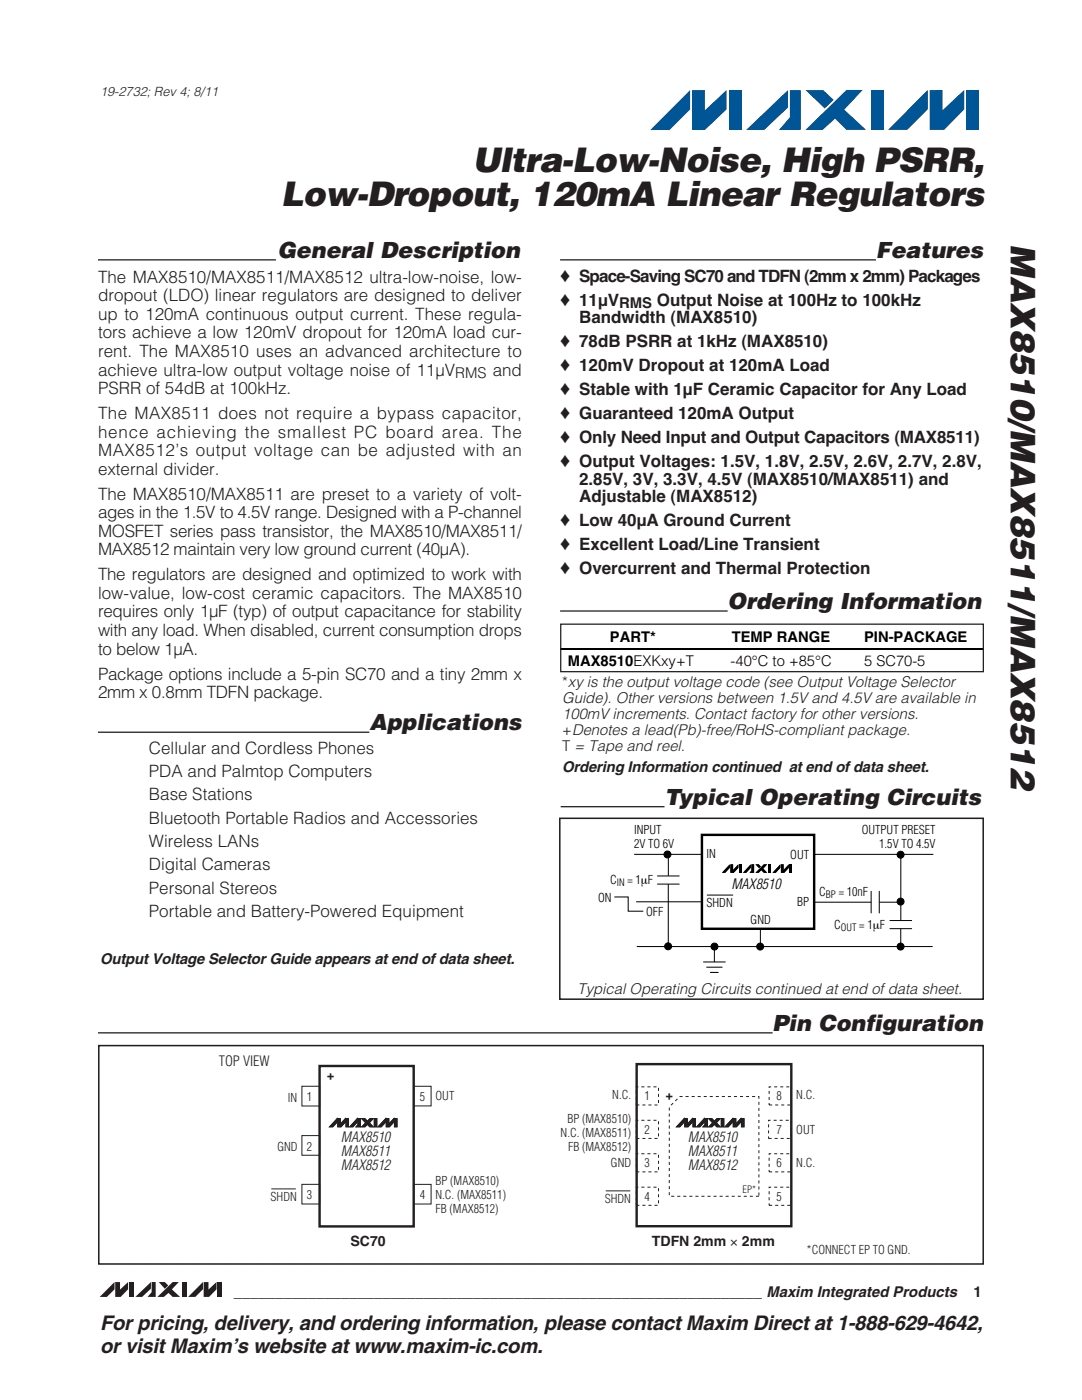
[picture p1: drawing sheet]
<svg xmlns="http://www.w3.org/2000/svg" width="216mm" height="279mm" viewBox="0 0 216 279" stroke-linecap="round" stroke-linejoin="round" font-family="sans-serif">
<defs><g id="words">
<g font-size="6.9" fill="#231f20">
<text x="94.3" y="34.3">Ultra-Low-Noise, High PSRR,</text>
<text x="56.1" y="41">Low-Dropout, 120mA Linear Regulators</text>
<text x="201.7" y="48.7" transform="rotate(90 201.7 48.7)">MAX8510/MAX8511/MAX8512</text>
</g>
<g font-size="4.5" fill="#231f20">
<text x="55.4" y="51.5">General Description</text>
<text x="174.8" y="51.5">Features</text>
<text x="145.2" y="121.5">Ordering Information</text>
<text x="73.7" y="145.7">Applications</text>
<text x="132.6" y="160.6">Typical Operating Circuits</text>
<text x="154.2" y="205.7">Pin Configuration</text>
</g>
<g font-size="4.1" fill="#231f20">
<text x="20" y="265.4">For pricing, delivery, and ordering information, please contact Maxim Direct at 1-888-629-4642,</text>
<text x="20" y="270">or visit Maxim’s website at www.maxim-ic.com.</text>
</g>
<g font-size="3.4" fill="#231f20">
<text x="19.6" y="56.4">The MAX8510/MAX8511/MAX8512 ultra-low-noise, low-</text>
<text x="111.8" y="56.2">♦ Space-Saving SC70 and TDFN (2mm x 2mm) Packages</text>
<text x="19.6" y="60.1">dropout (LDO) linear regulators are designed to deliver</text>
<text x="19.6" y="63.8">up to 120mA continuous output current. These regula-</text>
<text x="111.8" y="61">♦ 11µV</text>
<text x="115.6" y="64.5">Bandwidth (MAX8510)</text>
<text x="131.1" y="61">Output Noise at 100Hz to 100kHz</text>
<text x="19.6" y="67.6">tors achieve a low 120mV dropout for 120mA load cur-</text>
<text x="19.6" y="71.3">rent. The MAX8510 uses an advanced architecture to</text>
<text x="111.8" y="69.3">♦ 78dB PSRR at 1kHz (MAX8510)</text>
<text x="19.6" y="75">achieve ultra-low output voltage noise of 11µV</text>
<text x="98.3" y="75">and</text>
<text x="111.8" y="74.1">♦ 120mV Dropout at 120mA Load</text>
<text x="19.6" y="78.7">PSRR of 54dB at 100kHz.</text>
<text x="19.6" y="83.6">The MAX8511 does not require a bypass capacitor,</text>
<text x="111.8" y="78.9">♦ Stable with 1µF Ceramic Capacitor for Any Load</text>
<text x="111.8" y="83.7">♦ Guaranteed 120mA Output</text>
<text x="19.6" y="87.3">hence achieving the smallest PC board area. The</text>
<text x="111.8" y="88.5">♦ Only Need Input and Output Capacitors (MAX8511)</text>
<text x="19.6" y="91">MAX8512’s output voltage can be adjusted with an</text>
<text x="19.6" y="94.8">external divider.</text>
<text x="111.8" y="93.2">♦ Output Voltages: 1.5V, 1.8V, 2.5V, 2.6V, 2.7V, 2.8V,</text>
<text x="19.6" y="99.7">The MAX8510/MAX8511 are preset to a variety of volt-</text>
<text x="115.6" y="96.8">2.85V, 3V, 3.3V, 4.5V (MAX8510/MAX8511) and</text>
<text x="115.6" y="100.3">Adjustable (MAX8512)</text>
<text x="19.6" y="103.4">ages in the 1.5V to 4.5V range. Designed with a P-channel</text>
<text x="19.6" y="107.1">MOSFET series pass transistor, the MAX8510/MAX8511/</text>
<text x="111.8" y="105">♦ Low 40µA Ground Current</text>
<text x="19.6" y="110.8">MAX8512 maintain very low ground current (40µA).</text>
<text x="111.8" y="109.8">♦ Excellent Load/Line Transient</text>
<text x="19.6" y="115.8">The regulators are designed and optimized to work with</text>
<text x="19.6" y="119.5">low-value, low-cost ceramic capacitors. The MAX8510</text>
<text x="111.8" y="114.6">♦ Overcurrent and Thermal Protection</text>
<text x="19.6" y="123.2">requires only 1µF (typ) of output capacitance for stability</text>
<text x="19.6" y="126.9">with any load. When disabled, current consumption drops</text>
<text x="19.6" y="130.6">to below 1µA.</text>
<text x="19.6" y="135.6">Package options include a 5-pin SC70 and a tiny 2mm x</text>
<text x="19.6" y="139.3">2mm x 0.8mm TDFN package.</text>
<text x="29.7" y="150.4">Cellular and Cordless Phones</text>
<text x="29.7" y="155">PDA and Palmtop Computers</text>
<text x="29.7" y="159.7">Base Stations</text>
<text x="29.7" y="164.4">Bluetooth Portable Radios and Accessories</text>
<text x="29.7" y="169">Wireless LANs</text>
<text x="29.7" y="173.7">Digital Cameras</text>
<text x="29.7" y="178.3">Personal Stereos</text>
<text x="29.7" y="183">Portable and Battery-Powered Equipment</text>
</g>
<g font-size="3" fill="#231f20">
<text x="123.5" y="61.5">RMS</text>
<text x="90.8" y="75.4">RMS</text>
<text x="112.2" y="137.1">*xy is the output voltage code (see Output Voltage Selector</text>
<text x="112.2" y="140.3">Guide). Other versions between 1.5V and 4.5V are available in</text>
<text x="112.2" y="143.4">100mV increments. Contact factory for other versions.</text>
<text x="112.2" y="146.6">+Denotes a lead(Pb)-free/RoHS-compliant package.</text>
<text x="112.2" y="149.8">T = Tape and reel.</text>
<text x="112.2" y="154">Ordering Information continued at end of data sheet.</text>
<text x="20" y="192.3">Output Voltage Selector Guide appears at end of data sheet.</text>
<text x="115.2" y="198.3">Typical Operating Circuits continued at end of data sheet.</text>
<text x="46.7" y="258.8">________________________________________________________________ Maxim Integrated Products</text>
<text x="194.3" y="258.8">1</text>
</g>
<g font-size="2.9">
<text x="121.7" y="128.2">PART*</text>
<text x="146" y="128.2">TEMP RANGE</text>
<text x="172.4" y="128.2">PIN-PACKAGE</text>
<text x="113.3" y="132.9">MAX8510EXKxy+T</text>
<text x="145.8" y="132.9">-40°C to +85°C</text>
<text x="172.4" y="132.9">5 SC70-5</text>
</g>
<text font-size="2.8" x="145.9" y="177.4">MAX8510</text>
<g font-size="2.8" fill="#231f20">
<text x="43.7" y="212.8">TOP VIEW</text>
<text x="68" y="228">MAX8510</text>
<text x="137.3" y="228">MAX8510</text>
<text x="68" y="230.8">MAX8511</text>
<text x="68" y="233.6">MAX8512</text>
<text x="137.3" y="230.8">MAX8511</text>
<text x="137.3" y="233.6">MAX8512</text>
<text x="69.9" y="248.6">SC70</text>
<text x="130.1" y="248.7">TDFN 2mm × 2mm</text>
</g>
<text font-size="2.6" fill="#231f20" x="20" y="19.2">19-2732; Rev 4; 8/11</text>
<g font-size="2.4">
<text x="126.5" y="166.4">INPUT</text>
<text x="172" y="166.5">OUTPUT PRESET</text>
<text x="126.5" y="169.2">2V TO 6V</text>
<text x="141" y="171.3">IN</text>
<text x="157.7" y="171.4">OUT</text>
<text x="175.4" y="169.3">1.5V TO 4.5V</text>
<text x="121.7" y="176.4">C</text>
<text x="125.2" y="176.4">= 1μF</text>
<text x="163.5" y="178.9">C</text>
<text x="167.4" y="178.9">= 10nF</text>
<text x="119.3" y="180">ON</text>
<text x="128.9" y="182.7">OFF</text>
<text x="141" y="181">SHDN</text>
<text x="149.8" y="184.4">GND</text>
<text x="159" y="180.8">BP</text>
<text x="166.5" y="185.5">C</text>
<text x="171.5" y="185.5">= 1μF</text>
</g>
<g font-size="2.4" fill="#231f20">
<text x="65.3" y="214" transform="rotate(90 65.3 214)">+</text>
<text x="57.4" y="220">IN</text>
<text x="61.2" y="219.6">1</text>
<text x="83.8" y="219.6">5</text>
<text x="86.9" y="219.6">OUT</text>
<text x="122.2" y="219.4">N.C.</text>
<text x="128.6" y="219.5">1</text>
<text x="132.9" y="218.1" transform="rotate(90 132.9 218.1)">+</text>
<text x="155" y="219.5">8</text>
<text x="158.9" y="219.4">N.C.</text>
<text x="111.9" y="226.9">N.C. (MAX8511)</text>
<text x="113.2" y="224.1">BP (MAX8510)</text>
<text x="128.6" y="226.2">2</text>
<text x="154.9" y="226.2">7</text>
<text x="158.9" y="226.3">OUT</text>
<text x="55.3" y="229.7">GND</text>
<text x="61.2" y="229.6">2</text>
<text x="113.3" y="229.7">FB (MAX8512)</text>
<text x="121.9" y="232.9">GND</text>
<text x="128.6" y="232.9">3</text>
<text x="155" y="232.9">6</text>
<text x="158.9" y="232.9">N.C.</text>
<text x="54" y="239.6">SHDN</text>
<text x="61.2" y="239.4">3</text>
<text x="83.8" y="239.4">4</text>
<text x="86.9" y="236.4">BP (MAX8510)</text>
<text x="86.9" y="239.3">N.C. (MAX8511)</text>
<text x="128.6" y="239.7">4</text>
<text x="155" y="239.7">5</text>
<text x="86.9" y="242.1">FB (MAX8512)</text>
<text x="120.7" y="240">SHDN</text>
<text x="161" y="250.2">*CONNECT EP TO GND.</text>
</g>
<g font-size="2">
<text x="123.1" y="176.8">IN</text>
<text x="164.8" y="179.3">BP</text>
<text x="167.8" y="185.9">OUT</text>
</g>
<text font-size="2" fill="#231f20" x="148.2" y="238.1">EP*</text>
</g></defs>
<path d="M19.6 51.9h35.5M111.8 51.9h63M19.6 146.1h54.1" fill="none" stroke="#231f20" stroke-width=".26"/>
<path d="M19.9 254h25.9v5.1h-25.9z" fill="#fff"/>
<g fill="#231f20">
<path d="M27 258.8l3.1-2.9v1.3l-1.7 1.6z"/>
<path d="M30.3 255.9h.8v2.9h-1.7l.9-.9z"/>
<path d="M31.7 255.9h1.2l.7 .6-.7 .7z"/>
<path d="M31.4 258.8l3.1-2.9h1.2l-1.4 1.4 1.6 1.5h-1.4l-.9-.8-.9 .8z"/>
<path d="M22.9 255.9v1.4l-1.6 1.5h-1.4z"/>
<path d="M23 255.9h1v1.5l1.6-1.5v1.4l-1.5 1.5h-1.1z"/>
<path d="M25.7 255.9h1v2.9h-1z"/>
<path d="M36.3 255.9h.9v2.9h-.9z"/>
<path d="M40.5 255.9v1.4l-1.5 1.5h-1.5z"/>
<path d="M40.6 255.9h1v1.5l1.6-1.5v1.4l-1.5 1.5h-1.1z"/>
<path d="M43.3 255.9h1v2.9h-1z"/>
</g>
<path d="M60.2 226.6h3.6v4h-3.6z" fill="#fff"/>
<path d="M60.2 226.6h3.6v4h-3.6z" fill="none" stroke="#231f20" stroke-width=".2"/>
<path d="M60.2 236.4h3.6v3.9h-3.6z" fill="#fff"/>
<path d="M60.2 236.4h3.6v3.9h-3.6z" fill="none" stroke="#231f20" stroke-width=".2"/>
<path d="M82.5 236.4h3.5v3.9h-3.5z" fill="#fff"/>
<path d="M82.5 236.4h3.5v3.9h-3.5z" fill="none" stroke="#231f20" stroke-width=".2"/>
<path d="M60.2 216.8h3.6v3.9h-3.6z" fill="#fff"/>
<path d="M60.2 216.8h3.6v3.9h-3.6z" fill="none" stroke="#231f20" stroke-width=".2"/>
<path d="M82.5 216.8h3.5v3.9h-3.5z" fill="#fff"/>
<path d="M82.5 216.8h3.5v3.9h-3.5z" fill="none" stroke="#231f20" stroke-width=".2"/>
<path d="M63.8 212.7h18.7v32.1h-18.7z" fill="none" stroke="#231f20" stroke-width=".48"/>
<path d="M67.3 223.3v.6l-.9 1h-.6z" fill="#231f20"/>
<path d="M67.3 223.3v.6l-.9 1h-.6z" fill="none" stroke="#231f20" stroke-width=".2"/>
<path d="M67.3 223.3v.6l-.9 1h-.6z" fill="#231f20"/>
<path d="M67.3 223.3v.6l-.9 1h-.6z" fill="none" stroke="#231f20" stroke-width=".2"/>
<path d="M67.4 223.3h.5v1l1-1v.6l-.9 1h-.6z" fill="#231f20"/>
<path d="M67.4 223.3h.5v1l1-1v.6l-.9 1h-.6z" fill="none" stroke="#231f20" stroke-width=".2"/>
<path d="M67.4 223.3h.5v1l1-1v.6l-.9 1h-.6z" fill="#231f20"/>
<path d="M67.4 223.3h.5v1l1-1v.6l-.9 1h-.6z" fill="none" stroke="#231f20" stroke-width=".2"/>
<path d="M69 223.3h.5v1.6h-.5z" fill="#231f20"/>
<path d="M69 223.3h.5v1.6h-.5z" fill="none" stroke="#231f20" stroke-width=".2"/>
<path d="M69 223.3h.5v1.6h-.5z" fill="#231f20"/>
<path d="M69 223.3h.5v1.6h-.5z" fill="none" stroke="#231f20" stroke-width=".2"/>
<path d="M71.3 223.3v.6l-.9 1h-.6z" fill="#231f20"/>
<path d="M71.3 223.3v.6l-.9 1h-.6z" fill="none" stroke="#231f20" stroke-width=".2"/>
<path d="M71.3 223.3v.6l-.9 1h-.6z" fill="#231f20"/>
<path d="M71.3 223.3v.6l-.9 1h-.6z" fill="none" stroke="#231f20" stroke-width=".2"/>
<path d="M71.4 223.3h.5v1.6h-.8l.3-.4z" fill="#231f20"/>
<path d="M71.4 223.3h.5v1.6h-.8l.3-.4z" fill="none" stroke="#231f20" stroke-width=".2"/>
<path d="M71.4 223.3h.5v1.6h-.8l.3-.4z" fill="#231f20"/>
<path d="M71.4 223.3h.5v1.6h-.8l.3-.4z" fill="none" stroke="#231f20" stroke-width=".2"/>
<path d="M73.8 223.3h.6l-.7 .8 .7 .8h-.6l-.5-.5-.5 .5h-.6z" fill="#231f20"/>
<path d="M73.8 223.3h.6l-.7 .8 .7 .8h-.6l-.5-.5-.5 .5h-.6z" fill="none" stroke="#231f20" stroke-width=".2"/>
<path d="M73.8 223.3h.6l-.7 .8 .7 .8h-.6l-.5-.5-.5 .5h-.6z" fill="#231f20"/>
<path d="M73.8 223.3h.6l-.7 .8 .7 .8h-.6l-.5-.5-.5 .5h-.6z" fill="none" stroke="#231f20" stroke-width=".2"/>
<path d="M72.2 223.3h.6l.4 .4-.3 .3z" fill="#231f20"/>
<path d="M72.2 223.3h.6l.4 .4-.3 .3z" fill="none" stroke="#231f20" stroke-width=".2"/>
<path d="M72.2 223.3h.6l.4 .4-.3 .3z" fill="#231f20"/>
<path d="M72.2 223.3h.6l.4 .4-.3 .3z" fill="none" stroke="#231f20" stroke-width=".2"/>
<path d="M74.7 223.3h.5v1.6h-.5z" fill="#231f20"/>
<path d="M74.7 223.3h.5v1.6h-.5z" fill="none" stroke="#231f20" stroke-width=".2"/>
<path d="M74.7 223.3h.5v1.6h-.5z" fill="#231f20"/>
<path d="M74.7 223.3h.5v1.6h-.5z" fill="none" stroke="#231f20" stroke-width=".2"/>
<path d="M77 223.3v.6l-.9 1h-.7z" fill="#231f20"/>
<path d="M77 223.3v.6l-.9 1h-.7z" fill="none" stroke="#231f20" stroke-width=".2"/>
<path d="M77 223.3v.6l-.9 1h-.7z" fill="#231f20"/>
<path d="M77 223.3v.6l-.9 1h-.7z" fill="none" stroke="#231f20" stroke-width=".2"/>
<path d="M77.1 223.3h.5v1l1-1v.6l-.9 1h-.6z" fill="#231f20"/>
<path d="M77.1 223.3h.5v1l1-1v.6l-.9 1h-.6z" fill="none" stroke="#231f20" stroke-width=".2"/>
<path d="M77.1 223.3h.5v1l1-1v.6l-.9 1h-.6z" fill="#231f20"/>
<path d="M77.1 223.3h.5v1l1-1v.6l-.9 1h-.6z" fill="none" stroke="#231f20" stroke-width=".2"/>
<path d="M78.7 223.3h.5v1.6h-.5z" fill="#231f20"/>
<path d="M78.7 223.3h.5v1.6h-.5z" fill="none" stroke="#231f20" stroke-width=".2"/>
<path d="M78.7 223.3h.5v1.6h-.5z" fill="#231f20"/>
<path d="M78.7 223.3h.5v1.6h-.5z" fill="none" stroke="#231f20" stroke-width=".2"/>
<path d="M136.5 223.3v.6l-.9 1h-.6z" fill="#231f20"/>
<path d="M136.5 223.3v.6l-.9 1h-.6z" fill="none" stroke="#231f20" stroke-width=".2"/>
<path d="M136.5 223.3v.6l-.9 1h-.6z" fill="#231f20"/>
<path d="M136.5 223.3v.6l-.9 1h-.6z" fill="none" stroke="#231f20" stroke-width=".2"/>
<path d="M136.6 223.3h.6v1l1-1v.6l-.9 1h-.7z" fill="#231f20"/>
<path d="M136.6 223.3h.6v1l1-1v.6l-.9 1h-.7z" fill="none" stroke="#231f20" stroke-width=".2"/>
<path d="M136.6 223.3h.6v1l1-1v.6l-.9 1h-.7z" fill="#231f20"/>
<path d="M136.6 223.3h.6v1l1-1v.6l-.9 1h-.7z" fill="none" stroke="#231f20" stroke-width=".2"/>
<path d="M138.3 223.3h.5v1.6h-.5z" fill="#231f20"/>
<path d="M138.3 223.3h.5v1.6h-.5z" fill="none" stroke="#231f20" stroke-width=".2"/>
<path d="M138.3 223.3h.5v1.6h-.5z" fill="#231f20"/>
<path d="M138.3 223.3h.5v1.6h-.5z" fill="none" stroke="#231f20" stroke-width=".2"/>
<path d="M140.5 223.3v.6l-.8 1h-.7z" fill="#231f20"/>
<path d="M140.5 223.3v.6l-.8 1h-.7z" fill="none" stroke="#231f20" stroke-width=".2"/>
<path d="M140.5 223.3v.6l-.8 1h-.7z" fill="#231f20"/>
<path d="M140.5 223.3v.6l-.8 1h-.7z" fill="none" stroke="#231f20" stroke-width=".2"/>
<path d="M140.7 223.3h.5v1.6h-.9l.4-.4z" fill="#231f20"/>
<path d="M140.7 223.3h.5v1.6h-.9l.4-.4z" fill="none" stroke="#231f20" stroke-width=".2"/>
<path d="M140.7 223.3h.5v1.6h-.9l.4-.4z" fill="#231f20"/>
<path d="M140.7 223.3h.5v1.6h-.9l.4-.4z" fill="none" stroke="#231f20" stroke-width=".2"/>
<path d="M143 223.3h.7l-.8 .8 .8 .8h-.7l-.5-.5-.5 .5h-.6z" fill="#231f20"/>
<path d="M143 223.3h.7l-.8 .8 .8 .8h-.7l-.5-.5-.5 .5h-.6z" fill="none" stroke="#231f20" stroke-width=".2"/>
<path d="M143 223.3h.7l-.8 .8 .8 .8h-.7l-.5-.5-.5 .5h-.6z" fill="#231f20"/>
<path d="M143 223.3h.7l-.8 .8 .8 .8h-.7l-.5-.5-.5 .5h-.6z" fill="none" stroke="#231f20" stroke-width=".2"/>
<path d="M141.4 223.3h.6l.5 .4-.4 .3z" fill="#231f20"/>
<path d="M141.4 223.3h.6l.5 .4-.4 .3z" fill="none" stroke="#231f20" stroke-width=".2"/>
<path d="M141.4 223.3h.6l.5 .4-.4 .3z" fill="#231f20"/>
<path d="M141.4 223.3h.6l.5 .4-.4 .3z" fill="none" stroke="#231f20" stroke-width=".2"/>
<path d="M143.9 223.3h.5v1.6h-.5z" fill="#231f20"/>
<path d="M143.9 223.3h.5v1.6h-.5z" fill="none" stroke="#231f20" stroke-width=".2"/>
<path d="M143.9 223.3h.5v1.6h-.5z" fill="#231f20"/>
<path d="M143.9 223.3h.5v1.6h-.5z" fill="none" stroke="#231f20" stroke-width=".2"/>
<path d="M146.2 223.3v.6l-.9 1h-.6z" fill="#231f20"/>
<path d="M146.2 223.3v.6l-.9 1h-.6z" fill="none" stroke="#231f20" stroke-width=".2"/>
<path d="M146.2 223.3v.6l-.9 1h-.6z" fill="#231f20"/>
<path d="M146.2 223.3v.6l-.9 1h-.6z" fill="none" stroke="#231f20" stroke-width=".2"/>
<path d="M146.3 223.3h.5v1l1-1v.6l-.9 1h-.6z" fill="#231f20"/>
<path d="M146.3 223.3h.5v1l1-1v.6l-.9 1h-.6z" fill="none" stroke="#231f20" stroke-width=".2"/>
<path d="M146.3 223.3h.5v1l1-1v.6l-.9 1h-.6z" fill="#231f20"/>
<path d="M146.3 223.3h.5v1l1-1v.6l-.9 1h-.6z" fill="none" stroke="#231f20" stroke-width=".2"/>
<path d="M147.9 223.3h.6v1.6h-.6z" fill="#231f20"/>
<path d="M147.9 223.3h.6v1.6h-.6z" fill="none" stroke="#231f20" stroke-width=".2"/>
<path d="M147.9 223.3h.6v1.6h-.6z" fill="#231f20"/>
<path d="M147.9 223.3h.6v1.6h-.6z" fill="none" stroke="#231f20" stroke-width=".2"/>
<path d="M54.1 237.3h4.9z" fill="#fff"/>
<path d="M54.1 237.3h4.9M120.9 237.7h4.9" fill="none" stroke="#231f20" stroke-width=".2"/>
<path d="M127 212.4h30.9v32.3h-30.9z" fill="none" stroke="#231f20" stroke-width=".48"/>
<path d="M127 216.9h4.4v3.6h-4.4zM153.5 216.9h4.4v3.6h-4.4zM127 230.3h4.4v3.6h-4.4zM127 223.6h4.4v3.6h-4.4zM127 236.9h4.4v3.6h-4.4zM133.5 220.9l2.2-2.1h15.7v19.9h-17.9zM153.4 223.6h4.4v3.6h-4.4zM153.5 230.3h4.4v3.6h-4.4zM153.5 236.9h4.4v3.6h-4.4z" fill="none" stroke="#231f20" stroke-width=".2" stroke-dasharray=".6 .6" stroke-linecap="butt"/>
<path d="M19.7 208.7h176.5v43.6h-176.5z" fill="none" stroke="#231f20" stroke-width=".3"/>
<path d="M19.6 206.1h134.6" fill="none" stroke="#231f20" stroke-width=".26"/>
<path d="M111.8 118.3h84.4v6h-84.4z" fill="#fff"/>
<path d="M111.8 121.9h33.4M111.9 161h20.7" fill="none" stroke="#231f20" stroke-width=".26"/>
<g fill="none" stroke="#000" stroke-width=".2">
<path d="M122.6 179h2.7v2.8h3M126.5 170.5h13.4M126.9 180h13.3M131.2 174.8h4.3M131.2 176.4h4.3M133.3 176.4v12.6M133.4 170.6v4.2M141.1 178.6h5.1M162.6 170.5h23.6M173.8 177.9v4.3M175.4 177.9v4.3M179.7 170.5v13.2"/>
<path d="M127.1 188.9h59M140.4 192h4.3M141 193h3.1M141.7 194.1h1.6M142.5 189v3M151.7 185.4v3.6M162.6 180.1h11.2M175.4 180.1h4.3M177.6 183.7h4.3M177.6 185.3h4.3M179.7 185.3v3.7"/>
</g>
<g fill="#000" stroke="#000" stroke-width=".2">
<circle cx="133.2" cy="170.5" r=".69"/>
<circle cx="179.7" cy="179.9" r=".69"/>
<circle cx="179.7" cy="170.6" r=".69"/>
<circle cx="133.3" cy="188.9" r=".69"/>
<circle cx="142.6" cy="188.9" r=".69"/>
<circle cx="151.7" cy="188.9" r=".69"/>
<circle cx="179.7" cy="188.9" r=".69"/>
</g>
<path d="M140.1 166.6h22.4v18.8h-22.4z" fill="none" stroke="#000" stroke-width=".48"/>
<path d="M145.6 172.5v.7l-.9 1h-.7zM145.7 172.5h.6v1.1l1-1.1v.7l-.9 1h-.7zM147.4 172.5h.6v1.7h-.6zM149.8 172.5v.7l-.9 1h-.7zM149.9 172.5h.6v1.7h-.9l.3-.4zM152.4 172.5h.7l-.8 .8 .8 .9h-.7l-.5-.5-.5 .5h-.7zM150.7 172.5h.7l.4 .4-.3 .3zM153.3 172.5h.6v1.7h-.6zM155.7 172.5v.7l-.9 1h-.7zM155.8 172.5h.6v1.1l1-1.1v.7l-.9 1h-.7zM157.5 172.5h.6v1.7h-.6z" fill="#000"/>
<path d="M111.7 163.3h84.5v36.1h-84.5z" fill="none" stroke="#231f20" stroke-width=".3"/>
<g fill="#fff">
<path d="M111.8 134.5h84.5v16.6h-84.5z"/>
<path d="M111.9 124.6h84.3v9.4h-84.3z"/>
</g>
<path d="M111.9 129.5h84.4" fill="none" stroke="#000" stroke-width=".2"/>
<path d="M111.9 124.6h84.3v9.4h-84.3z" fill="none" stroke="#231f20" stroke-width=".25"/>
<path d="M19.6 189.8h84.5v4.5h-84.5z" fill="#fff"/>
<g fill="#005596">
<path d="M148.9 25.9l8.3-7.9v3.5l-4.7 4.4z"/>
<path d="M157.6 18h2.2v7.9h-4.4l2.2-2.5z"/>
<path d="M160.7 18h3.6l2.1 1.9-1.8 1.8z"/>
<path d="M160.7 25.9l8.2-7.9h3.3l-3.7 3.9 4.3 4h-3.9l-2.3-2.2-2.5 2.2z"/>
<path d="M137.7 18v3.8l-4.1 4.1h-3.8z"/>
<path d="M138.1 18h2.6v4l4.3-4v3.8l-4.3 4.1h-2.6z"/>
<path d="M145.4 18h2.6v7.9h-2.6z"/>
<path d="M173.7 18h2.6v7.9h-2.6z"/>
<path d="M185.1 17.9v3.9l-4.1 4.1h-3.8z"/>
<path d="M185.5 18h2.6v4l4.3-4.1v3.9l-4 4.1h-2.9z"/>
<path d="M192.8 18h2.6v7.9h-2.6z"/>
</g>
<path d="M111.8 151.5h84.5v3.7h-84.5z" fill="#fff"/>
<use href="#words"/>
</svg>
